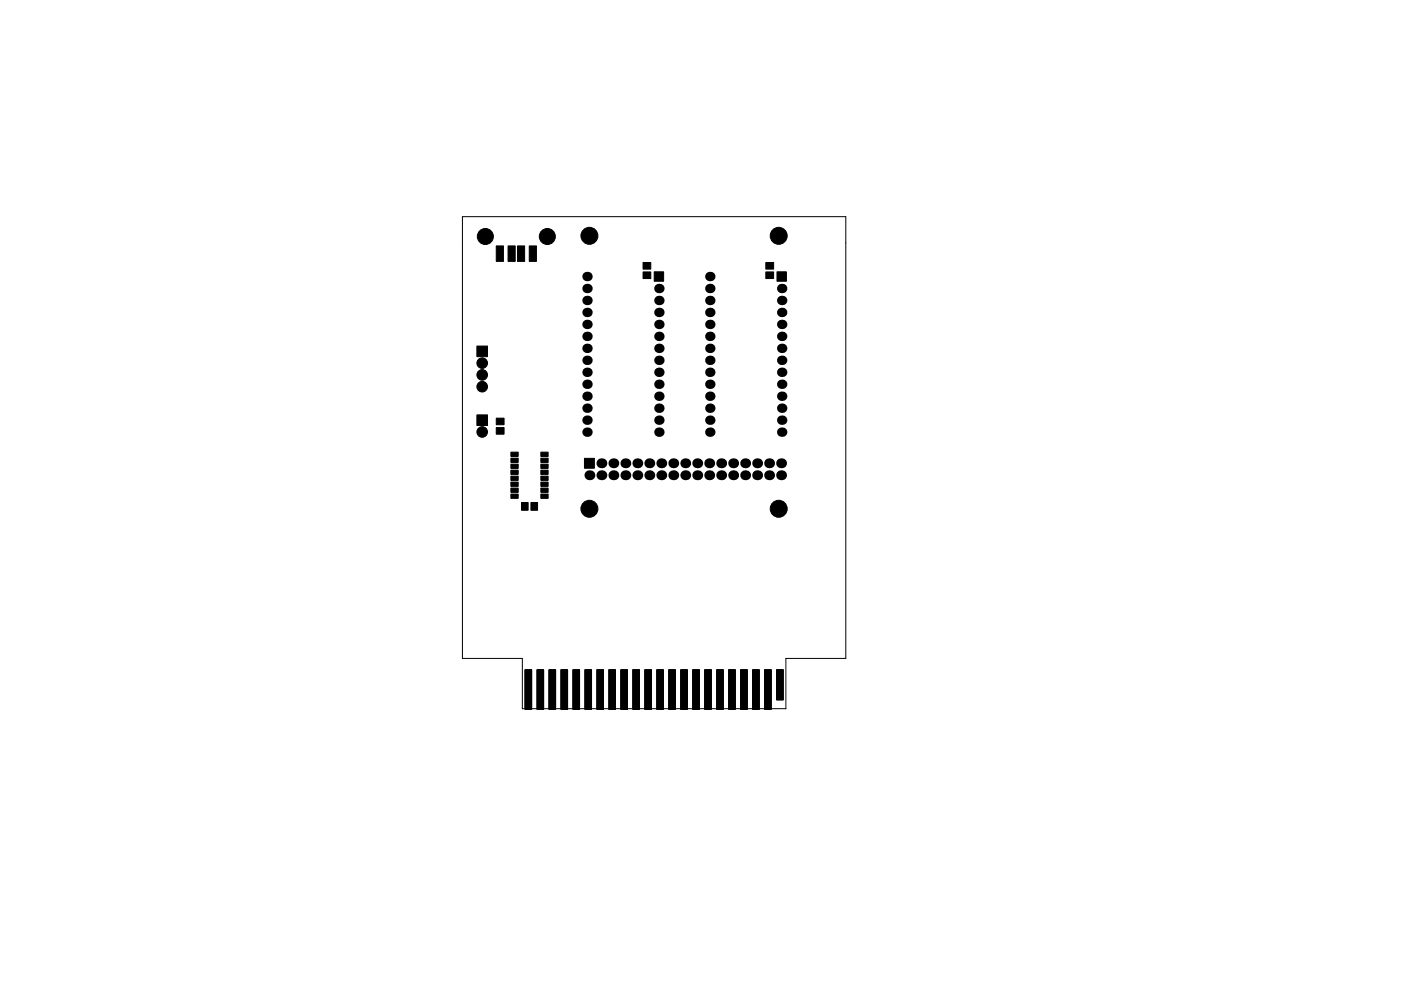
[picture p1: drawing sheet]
<svg xmlns="http://www.w3.org/2000/svg" width="297mm" height="210mm" viewBox="0 0 297 210" stroke-linecap="round" stroke-linejoin="round" font-family="sans-serif">
<path d="M98 46h81.3v93.7h-12.7v10.7h-55.9v-10.7h-12.7z" fill="none" stroke="#000" stroke-width=".21"/>
<g fill="#000" stroke="#000" stroke-width=".21">
<path d="M105.2 52.2h1.5v3.3h-1.5zM107.7 52.2h1.5v3.3h-1.5zM109.7 52.2h1.5v3.3h-1.5zM112.2 52.2h1.5v3.3h-1.5zM136.3 57.7h1.7v1.4h-1.7zM136.3 55.7h1.7v1.4h-1.7zM138.7 57.7h2v2h-2zM162.4 57.7h1.6v1.4h-1.6zM162.4 55.7h1.6v1.4h-1.6zM164.7 57.7h2v2h-2zM101.1 73.4h2.3v2.3h-2.3zM101.1 88h2.3v2.3h-2.3z"/>
<path d="M105.2 88.7h1.7v1.4h-1.7zM105.2 90.7h1.7v1.4h-1.7zM108.3 99.7h1.6v1h-1.6zM108.3 98.5h1.6v.9h-1.6zM108.3 97.2h1.6v.9h-1.6zM108.3 95.9h1.6v.9h-1.6zM114.7 95.9h1.5v.9h-1.5zM114.7 98.5h1.5v.9h-1.5zM114.7 99.7h1.5v1h-1.5zM114.7 97.2h1.5v.9h-1.5zM123.9 97.2h2.1v2.1h-2.1zM108.3 104.8h1.6v.9h-1.6z"/>
<path d="M108.3 103.6h1.6v.9h-1.6zM108.3 102.3h1.6v.9h-1.6zM108.3 101h1.6v.9h-1.6zM110.6 106.6h1.4v1.7h-1.4zM112.6 106.6h1.4v1.7h-1.4zM114.7 101h1.5v.9h-1.5zM114.7 102.3h1.5v.9h-1.5zM114.7 103.6h1.5v.9h-1.5zM114.7 104.8h1.5v.9h-1.5zM111.3 142.1h1.4v8.4h-1.4zM113.9 142.1h1.4v8.4h-1.4zM116.4 142.1h1.4v8.4h-1.4z"/>
<path d="M118.9 142.1h1.4v8.4h-1.4zM121.5 142.1h1.4v8.4h-1.4zM124 142.1h1.4v8.4h-1.4zM126.6 142.1h1.4v8.4h-1.4zM129.1 142.1h1.4v8.4h-1.4zM131.6 142.1h1.4v8.4h-1.4zM134.2 142.1h1.4v8.4h-1.4zM136.7 142.1h1.4v8.4h-1.4zM139.3 142.1h1.4v8.4h-1.4zM141.8 142.1h1.4v8.4h-1.4zM144.3 142.1h1.4v8.4h-1.4zM146.9 142.1h1.4v8.4h-1.4z"/>
<path d="M149.4 142.1h1.4v8.4h-1.4zM152 142.1h1.4v8.4h-1.4zM154.5 142.1h1.4v8.4h-1.4zM157 142.1h1.4v8.4h-1.4zM159.6 142.1h1.4v8.4h-1.4zM162.1 142.1h1.4v8.4h-1.4zM164.7 142.1h1.4v6.4h-1.4z"/>
<circle cx="102.9" cy="50.2" r="1.7"/>
<circle cx="116" cy="50.2" r="1.7"/>
<circle cx="125" cy="50" r="1.8"/>
<circle cx="165.1" cy="50" r="1.8"/>
<circle cx="102.2" cy="79.5" r="1.12"/>
<circle cx="102.2" cy="77" r="1.13"/>
<circle cx="102.2" cy="91.6" r="1.13"/>
<circle cx="102.2" cy="82" r="1.13"/>
<circle cx="125" cy="107.9" r="1.8"/>
<circle cx="165.1" cy="107.9" r="1.8"/>
</g>
<g fill="#000">
<circle cx="124.5" cy="58.7" r="1"/>
<circle cx="150.5" cy="58.7" r="1"/>
<circle cx="124.5" cy="76.4" r="1"/>
<circle cx="124.5" cy="66.3" r="1"/>
<circle cx="124.5" cy="63.7" r="1"/>
<circle cx="124.5" cy="79" r="1"/>
<circle cx="124.5" cy="71.4" r="1"/>
<circle cx="124.5" cy="68.8" r="1"/>
<circle cx="124.5" cy="73.9" r="1"/>
<circle cx="124.5" cy="61.2" r="1"/>
<circle cx="139.7" cy="66.3" r="1"/>
<circle cx="139.7" cy="73.9" r="1"/>
<circle cx="139.7" cy="79" r="1"/>
<circle cx="139.7" cy="63.7" r="1"/>
<circle cx="139.7" cy="76.4" r="1"/>
<circle cx="139.7" cy="68.8" r="1"/>
<circle cx="139.7" cy="71.4" r="1"/>
<circle cx="139.7" cy="61.2" r="1"/>
<circle cx="150.5" cy="76.4" r="1"/>
<circle cx="150.5" cy="79" r="1"/>
<circle cx="150.5" cy="73.9" r="1"/>
<circle cx="150.5" cy="71.4" r="1"/>
<circle cx="150.5" cy="66.3" r="1"/>
<circle cx="150.5" cy="61.2" r="1"/>
<circle cx="150.5" cy="68.8" r="1"/>
<circle cx="150.5" cy="63.7" r="1"/>
<circle cx="165.7" cy="61.2" r="1"/>
<circle cx="165.7" cy="76.4" r="1"/>
<circle cx="165.7" cy="63.7" r="1"/>
<circle cx="165.7" cy="71.4" r="1"/>
<circle cx="165.7" cy="73.9" r="1"/>
<circle cx="165.7" cy="79" r="1"/>
<circle cx="165.7" cy="66.3" r="1"/>
<circle cx="165.7" cy="68.8" r="1"/>
<circle cx="124.5" cy="91.7" r="1"/>
<circle cx="124.5" cy="86.6" r="1"/>
<circle cx="124.5" cy="84.1" r="1"/>
<circle cx="124.5" cy="81.5" r="1"/>
<circle cx="124.5" cy="89.1" r="1"/>
<circle cx="127.5" cy="98.3" r="1.05"/>
<circle cx="130" cy="98.3" r="1.05"/>
<circle cx="132.6" cy="98.3" r="1.05"/>
<circle cx="135.1" cy="98.3" r="1.05"/>
<circle cx="137.7" cy="98.3" r="1.05"/>
<circle cx="139.7" cy="81.5" r="1"/>
<circle cx="139.7" cy="91.7" r="1"/>
<circle cx="139.7" cy="86.6" r="1"/>
<circle cx="139.7" cy="89.1" r="1"/>
<circle cx="139.7" cy="84.1" r="1"/>
<circle cx="140.2" cy="98.3" r="1.05"/>
<circle cx="142.7" cy="98.3" r="1.05"/>
<circle cx="145.3" cy="98.3" r="1.05"/>
<circle cx="147.8" cy="98.3" r="1.05"/>
<circle cx="150.4" cy="98.3" r="1.05"/>
<circle cx="150.5" cy="86.6" r="1"/>
<circle cx="150.5" cy="89.1" r="1"/>
<circle cx="150.5" cy="91.7" r="1"/>
<circle cx="150.5" cy="84.1" r="1"/>
<circle cx="150.5" cy="81.5" r="1"/>
<circle cx="152.9" cy="98.3" r="1.05"/>
<circle cx="155.4" cy="98.3" r="1.05"/>
<circle cx="158" cy="98.3" r="1.05"/>
<circle cx="160.5" cy="98.3" r="1.05"/>
<circle cx="163.1" cy="98.3" r="1.05"/>
<circle cx="165.6" cy="98.3" r="1.05"/>
<circle cx="165.7" cy="84.1" r="1"/>
<circle cx="165.7" cy="86.6" r="1"/>
<circle cx="165.7" cy="81.5" r="1"/>
<circle cx="165.7" cy="91.7" r="1"/>
<circle cx="165.7" cy="89.1" r="1"/>
<circle cx="125" cy="100.8" r="1.05"/>
<circle cx="127.5" cy="100.8" r="1.05"/>
<circle cx="130" cy="100.8" r="1.05"/>
<circle cx="132.6" cy="100.8" r="1.05"/>
<circle cx="135.1" cy="100.8" r="1.05"/>
<circle cx="137.7" cy="100.8" r="1.05"/>
<circle cx="140.2" cy="100.8" r="1.05"/>
<circle cx="142.7" cy="100.8" r="1.05"/>
<circle cx="145.3" cy="100.8" r="1.05"/>
<circle cx="147.8" cy="100.8" r="1.05"/>
<circle cx="150.4" cy="100.8" r="1.05"/>
<circle cx="152.9" cy="100.8" r="1.05"/>
<circle cx="155.4" cy="100.8" r="1.05"/>
<circle cx="158" cy="100.8" r="1.05"/>
<circle cx="160.5" cy="100.8" r="1.05"/>
<circle cx="163.1" cy="100.8" r="1.05"/>
<circle cx="165.6" cy="100.8" r="1.05"/>
</g>
</svg>
